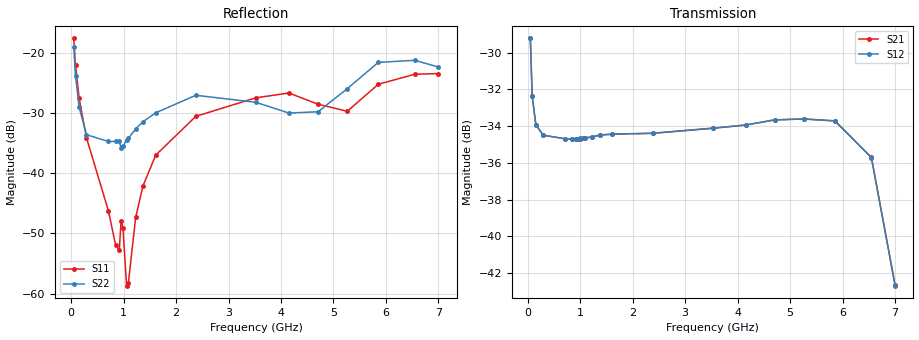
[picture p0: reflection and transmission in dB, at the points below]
! Integrated Device Technology
! Corporate Headquarters
! 6024 Silver Creek Valley Road
! San Jose, CA 95138  USA
! Phone:  1-408-284-8200
! Toll Free:  1-800-223-1366
! Webpage:  http://www.idt.com/
! Timing and RF Division
! 515 Groton Road, Suite 102
! Westford, MA 01886-6024
! Device:  F2258
! Description: Voltage Variable RF Attenuator
! Frequency:  50.0 -  6000.00 MHz
! Package:  3x3 mm Thin QFN Plastic Package: 16 pin
! Ports:  2 RF, 2 DC
!  Pin  1  = NC
!  Pin  2  = NC
!  Pin  3  = RF2  = Port 2
!  Pin  4  = GND
!  Pin  5  = Vdd
!  Pin  6  = NC
!  Pin  7  = VCTRL
!  Pin  8  = NC
!  Pin  9  = GND
!  Pin 10  = RF1  = Port 1
!  Pin 11  = NC
!  Pin 12  = NC
!  Pin 13  = NC
!  Pin 14  = NC
!  Pin 15  = NC
!  Pin 16  = NC
! Vcntrl:  1.930 Volts
! Vdd:  +3.300 Volts
! Current:  1.155 mA
! Data:  The device was measured on a the F2258 evaluation board which has
!  individual transmission lines to the RF pins.  Data was collected
!  using a calibrated network analyzer.  The evaluation board was
!  de-embedded using a TRL calibration technique.
!  The reference plane is the edge of the package pin.
! Misc:  SN 10
!  Action Tracker AT0285
! Date Measured:  2014-12-10
! Date:  2016-01-13  MJV
! Note:
!  Integrated Device Technology supplies this data as a sample of measured
!  data at the package pin for this product.  Your particular data for this
!  product may vary.
!  Data was taken at 25 degrees C.
!  Integrated Device Technology reserves the right to change this data at anytime.
!Freq_(GHz)  S11M_(dB)  S11P_(deg)  S21M_(dB)  S21P_(deg)  S12M_(dB)  S12P_(deg)  S22M_(dB)  S22P_(deg)
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# GHz S dB R 50
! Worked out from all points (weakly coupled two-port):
!   201 points, 50 MHz to 7 GHz, reference 50 ohm
!   highest |S21| = -29.22 dB at 50 MHz (marker M1); lowest = -42.7 dB at 7 GHz (marker M2)
!   lowest |S11| = -58.7 dB at 1.058 GHz (marker M3), VSWR 1.00, Z = 49.9 + j0.051 ohm
!   |S11| at or under -10 dB: start of sweep to end of sweep
!   |S22| runs from -35.7 to -18.9 dB; largest |S21 - S12| = 6.8e-05
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0.05  -17.55 -110.8  -29.22 -65.4  -29.22 -65.4  -18.92 -105.5
0.08475  -21.97 -107.3  -32.35 -46.1  -32.34 -46.1  -23.80 -92.5
0.15425  -27.55 -107.7  -33.92 -28.0  -33.92 -28.0  -29.01 -75.2
0.29325  -34.08 -112.8  -34.49 -16.2  -34.49 -16.2  -33.57 -46.7
0.71025  -46.19 -135.8  -34.69 -9.4  -34.69 -9.4  -34.70 -0.1
0.84925  -51.92 -172.6  -34.70 -8.9  -34.69 -8.9  -34.69 4.3
0.91875  -52.80 149.4  -34.69 -8.8  -34.68 -8.8  -34.69 5.0
0.9535  -47.86 -161.3  -34.70 -8.7  -34.69 -8.7  -35.72 14.0
0.98825  -49.02 -173.1  -34.68 -8.6  -34.67 -8.6  -35.53 12.3
1.05775  -58.69 153.9  -34.66 -8.6  -34.66 -8.5  -34.45 12.9
1.0925  -58.21 114.7  -34.65 -8.5  -34.64 -8.5  -34.19 13.1
1.2315  -47.31 44.3  -34.59 -8.7  -34.58 -8.7  -32.60 12.6
1.3705  -42.08 35.8  -34.49 -9.2  -34.48 -9.2  -31.41 12.9
1.61375  -36.97 32.0  -34.44 -10.6  -34.43 -10.6  -29.93 11.9
2.37825  -30.51 47.8  -34.39 -14.6  -34.39 -14.6  -27.02 15.1
3.525  -27.43 91.5  -34.11 -21.6  -34.12 -21.5  -28.19 39.7
4.1505  -26.64 104.9  -33.94 -26.2  -33.94 -26.2  -29.97 49.1
4.7065  -28.50 95.5  -33.66 -31.0  -33.66 -31.0  -29.76 29.7
5.2625  -29.68 54.1  -33.61 -37.1  -33.61 -37.1  -25.92 -2.1
5.85325  -25.19 29.7  -33.72 -47.4  -33.71 -47.4  -21.55 -16.4
6.54825  -23.52 45.0  -35.70 -67.0  -35.71 -67.0  -21.20 -48.7
7  -23.40 84.4  -42.65 -63.2  -42.69 -62.8  -22.32 -126.6
